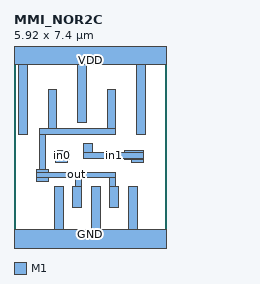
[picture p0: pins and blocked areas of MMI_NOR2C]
MACRO MMI_NOR2C
	CLASS CORE ;
	FOREIGN MMI_NOR2C 0 0 ;
	SIZE 5.92 BY 7.4 ;
	SYMMETRY X Y ;
	SITE CORE1 ;
	PIN out
		DIRECTION output ;
		USE SIGNAL ;
		PORT
			LAYER M1 ;
			RECT 1.33 4.41 1.67 5.94 ;
			LAYER M1 ;
			RECT 3.63 4.41 3.97 5.94 ;
			LAYER M1 ;
			RECT 1.01 4.18 3.97 4.41 ;
			LAYER M1 ;
			RECT 1.01 2.815 1.24 4.18 ;
			LAYER M1 ;
			RECT 0.885 2.725 1.335 2.815 ;
			LAYER M1 ;
			RECT 0.885 2.495 3.965 2.725 ;
			LAYER M1 ;
			RECT 0.885 2.365 1.335 2.495 ;
			LAYER M1 ;
			RECT 2.405 2.17 2.635 2.495 ;
			LAYER M1 ;
			RECT 2.295 1.33 2.635 2.17 ;
			LAYER M1 ;
			RECT 3.735 2.17 3.965 2.495 ;
			LAYER M1 ;
			RECT 3.735 1.33 4.075 2.17 ;
		END
		AntennaDiffArea 2.9808 ;
	END out
	PIN in1
		DIRECTION input ;
		USE SIGNAL ;
		PORT
			LAYER M1 ;
			RECT 2.72 3.495 3.06 3.82 ;
			LAYER M1 ;
			RECT 4.585 3.55 5.035 3.555 ;
			LAYER M1 ;
			RECT 4.3 3.495 5.035 3.55 ;
			LAYER M1 ;
			RECT 2.72 3.265 5.035 3.495 ;
			LAYER M1 ;
			RECT 4.3 3.21 5.035 3.265 ;
			LAYER M1 ;
			RECT 4.585 3.105 5.035 3.21 ;
		END
		AntennaGateArea 1.656 ;
	END in1
	PIN GND
		DIRECTION inout ;
		USE GROUND ;
		PORT
			LAYER M1 ;
			RECT 1.575 0.5 1.915 2.17 ;
			LAYER M1 ;
			RECT 3.015 0.5 3.355 2.17 ;
			LAYER M1 ;
			RECT 4.455 0.5 4.795 2.17 ;
			LAYER M1 ;
			RECT 0 -0.5 5.92 0.5 ;
		END
	END GND
	PIN VDD
		DIRECTION inout ;
		USE POWER ;
		PORT
			LAYER M1 ;
			RECT 0 6.9 5.92 7.9 ;
			LAYER M1 ;
			RECT 0.18 4.18 0.52 6.9 ;
			LAYER M1 ;
			RECT 2.48 4.66 2.82 6.9 ;
			LAYER M1 ;
			RECT 4.78 4.18 5.12 6.9 ;
		END
	END VDD
	PIN in0
		DIRECTION input ;
		USE SIGNAL ;
		PORT
			LAYER M1 ;
			RECT 1.625 3.55 2.075 3.555 ;
			LAYER M1 ;
			RECT 1.625 3.21 2.15 3.55 ;
			LAYER M1 ;
			RECT 1.625 3.105 2.075 3.21 ;
		END
		AntennaGateArea 1.656 ;
	END in0
	OBS
	END
END MMI_NOR2C
